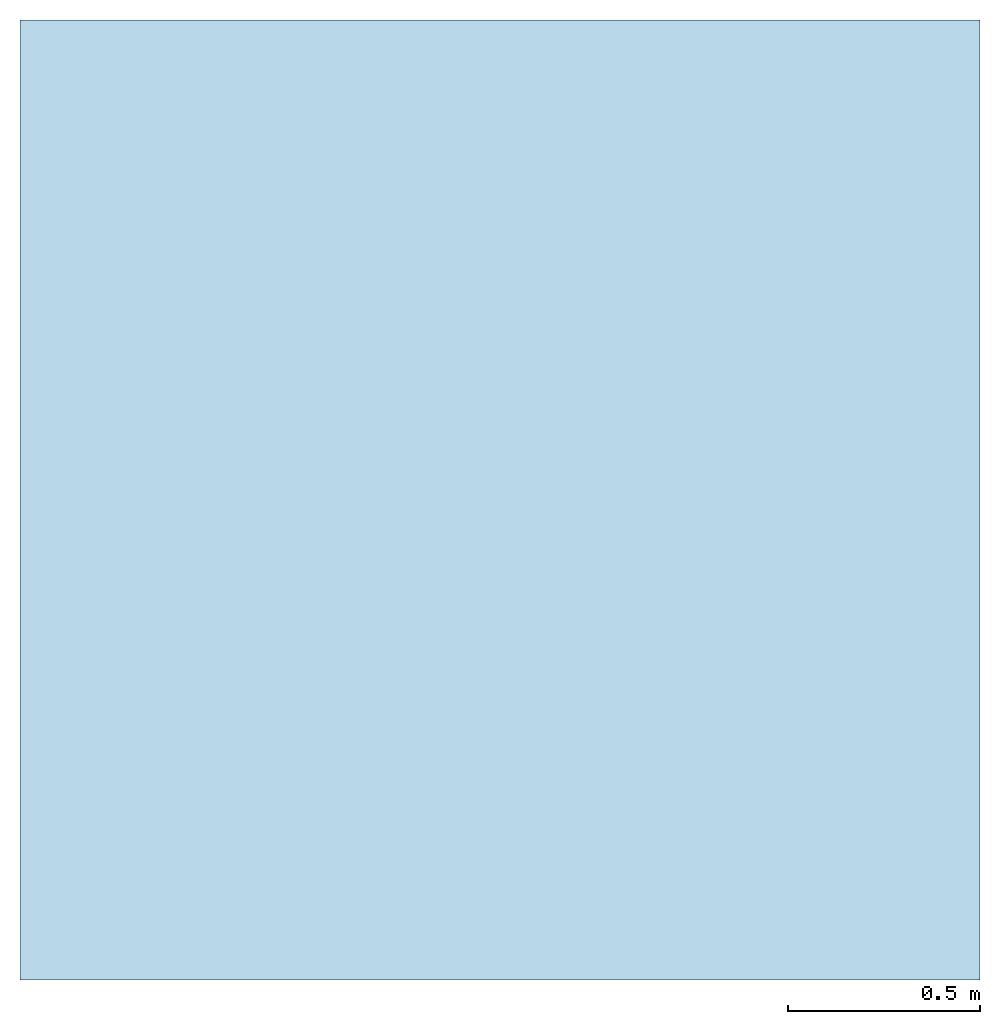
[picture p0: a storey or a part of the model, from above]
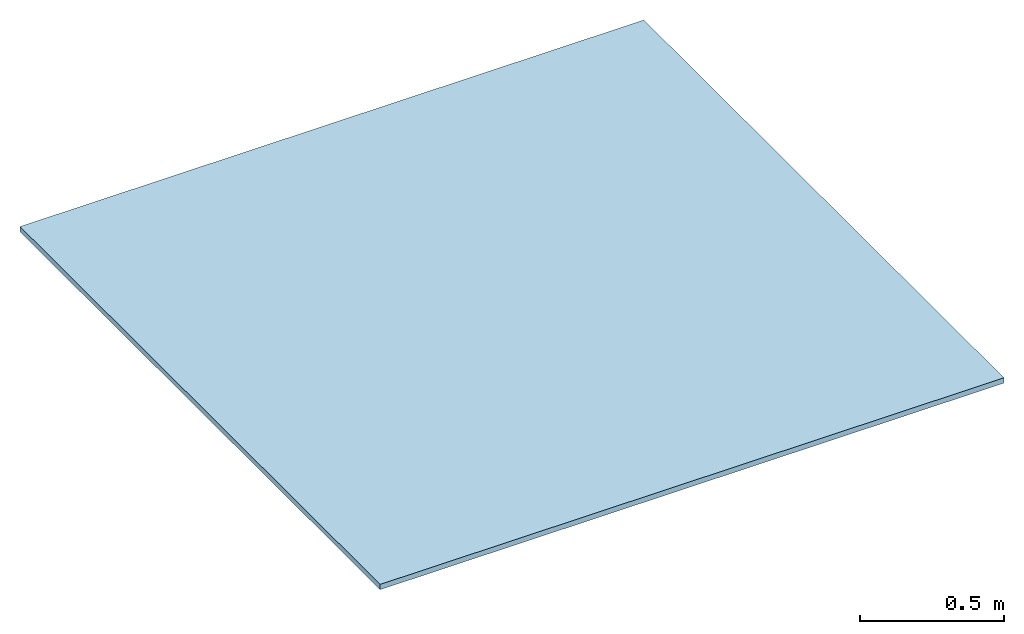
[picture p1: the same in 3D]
Properties of the parts of a building model (IFC2X3)

# File
Description: ViewDefinition[CoordinationView]
Time: 2019-06-13T11:28:18
Author: NBS
Written by: Xbim.Ifc File Processor version 2.4.1.0
Made in: Xbim version 2.4.1.0
Authorization: Add company name here

# IfcSlab: NBS_CompositePrime_HardwoodDeckBoards_HDDeckDualSystem
In: Default building
Type - PredefinedType: FLOOR; Material: NBS_CompositePrime_HardwoodDeckBoards_HDDeckDualSystem 22.5 mm
Type - xbim_MaterialFunctionAssignment - MaterialFunctionAssignment: 0: Finish1
Type - NBS_Data - 28DaysImmersionMaxSwelling: 0.82% in thickness, 0.04% in width, 0.09% in length; 28DaysImmersionMeanSwelling: 0.65% in thickness, 0.02% in width, 0.06 in length; 28DaysImmersionWaterAbsorption: Mean: 1.1%, Max: 1.2%; BendingStrength: 25.7 Mpa; BoardOneSideColours: Oak, walnut; BoardTwoSideColours: Antique, carbon; BoilingTest(5hours)WaterAbsorptionInWeight: Mean: 1.5%, Min: 1.6%; CharpyImpactStrength: 3.4 kj/m²; Deflection: Mean: 0.61 mm, Min: 0.71 mm; Density: 1.279 g/cm³; FallingMassImpactMaxCrackLength: No crack; FallingMassImpactMaxResidualIndentation: 0.13 mm; MaximumLoad: Mean: 4179 N, Min: 3836 N; ModulusOfElasticity: 3.7 Gpa; PendulumDryHorizontal: Mean: 79, Min: 78; PendulumDryLongitudinal: Mean: 67, Min: 66; PendulumWetHorizontal: Mean: 40, Min: 38; PendulumWetLongitudinal: Mean: 38, Min: 36; SlipResistanceOilWetRampTest: R10: 12.8°; SmokeProduction: s2; SuppliedBy: Composite Prime; TensileStrength: 16 Mpa
Type - COBie - AccessibilityPerformance: n/a; AssetType: Fixed; Category: Pr_25_71_97_37:Hardwood deck boards; CodePerformance: EN 15534-1: 2014 Section 6.4.2, CEN/TS 15676:2007, EN 15534-4:2014 Section 4.4,DIN 51130:2014, EN 15534-1:2014 Annex A, EN 15534-4:2014 Section 4.5.2, EN 15534-1:2014 Section 7.2, ISO 527-2:2012, EN 15534-1:2014 Section 7.1.2.1, EN 15534-4:2014 Section 4.5.1, EN 15534-1:2014 Section 7.1.1, EN ISO 11925-2:2010 Exposure = 15 s, EN 15534-1:2014 Section 8.3.3, EN 15534-4:2014 Section 4.5.5, EN 15534-1:2014 Section 8.3.1, EN 15534-1:2014 Section 6.2, ISO 1183-1:2012 Method A, ISO 179-1/1fU, EN 13501-1; Color: n/a; Constituents: n/a; Description: Natural wood grain composite decking; DurationUnit: year; ExpectedLife: n/a; Features: Slip resistant, free from hazardous substances, will not rot or decay, will not warp bend or splinter, requires no staining, treating or painting, friendly to the environment; Grade: n/a; Manufacturer: hello@composite-prime.com; Material: Plastic; ModelNumber: n/a; ModelReference: HD Deck Dual System; Name: HardwoodDeckBoards_HDDeckDualSystem_CompositePrime; NominalHeight: 22.5 mm; NominalLength: 3600 mm; NominalWidth: 143 mm; ReplacementCost: n/a; Shape: Rectangle; Size: 22.5 x 3600 x 143 mm; SustainabilityPerformance: FSC 100% certified; WarrantyDescription: Residential - 25 years, commercial - 10 years; WarrantyDurationLabor: n/a; WarrantyDurationParts: n/a; WarrantyDurationUnit: year; WarrantyGuarantorLabor: n/a; WarrantyGuarantorParts: n/a
Type - Pset_CoveringCommon - AcousticRating: n/a; Combustible: yes; Finish: n/a; FireRating: D fl; FlammabilityRating: D fl -s2; FragilityRating: n/a; IsExternal: yes; Reference: n/a; SurfaceSpreadOfFlame: n/a; ThermalTransmittance: 0
Type - BOS_General - Author: NBS; BIMObjectName: NBS_CompositePrime_HardwoodDeckBoards_HDDeckDualSystem; ManufacturerName: Composite Prime; ManufacturerURL: https://www.composite-prime.com/; NBSCertification: www.nationalbimlibrary.com/cert/tlknijsz; NBSDescription: Hardwood deck boards; NBSReference: 45-45-95/315; ProductInformation: https://www.composite-prime.com/wp-content/uploads/2018/12/HD-Deck-Dual_A4-Flyer_web-version.pdf; Revision: n/a; Uniclass2015Code: Pr_25_71_97_37; Uniclass2015Title: Hardwood deck boards; Uniclass2015Version: Products v1.13; Version: 1
Type - IFC - IfcExportAs: IfcCoveringType; IfcExportType: FLOORING
COBie - AssetIdentifier: n/a; BarCode: n/a; InstallationDate: 1900-12-31T23:59:59; SerialNumber: n/a; TagNumber: n/a; WarrantyStartDate: 1900-12-31T23:59:59
